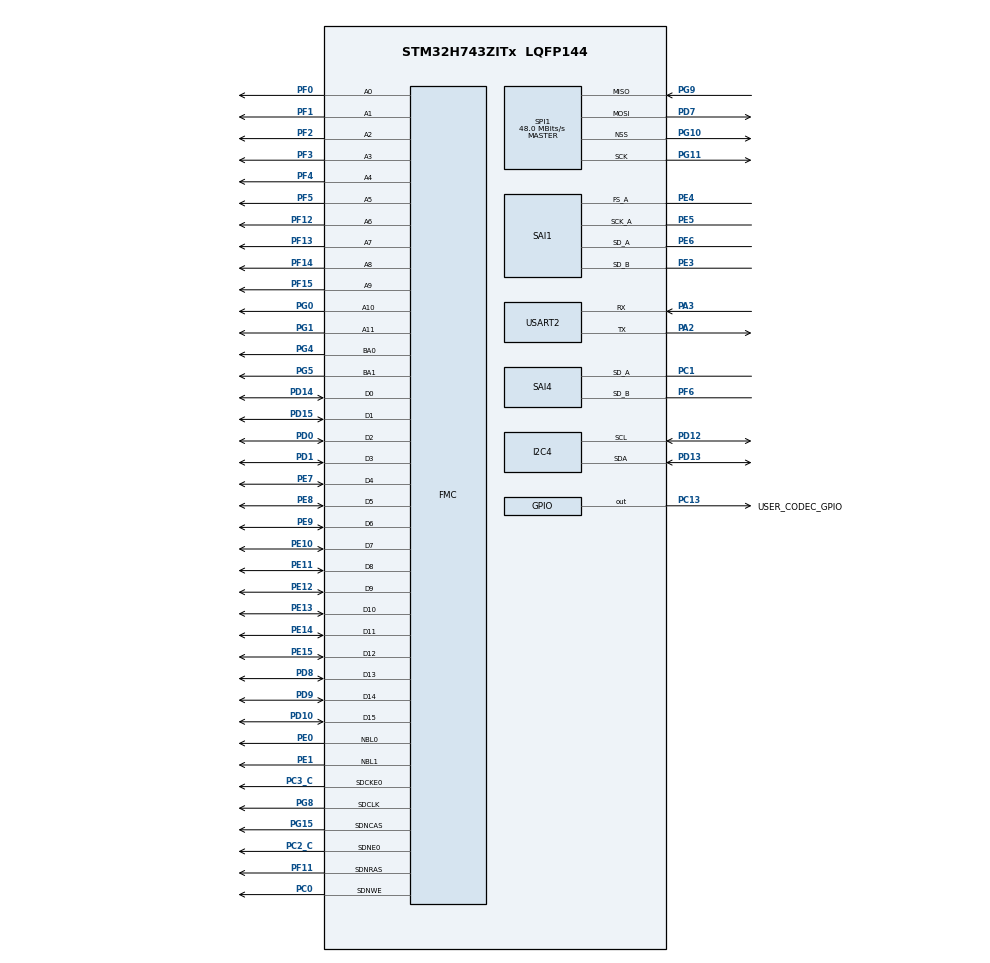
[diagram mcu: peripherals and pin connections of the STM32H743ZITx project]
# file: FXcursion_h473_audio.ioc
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Bdma.Request0=SAI4_A
Bdma.Request1=SAI4_B
Bdma.RequestsNb=2
Bdma.SAI4_A.0.Direction=DMA_PERIPH_TO_MEMORY
Bdma.SAI4_A.0.EventEnable=DISABLE
Bdma.SAI4_A.0.Instance=BDMA_Channel0
Bdma.SAI4_A.0.MemDataAlignment=DMA_MDATAALIGN_HALFWORD
Bdma.SAI4_A.0.MemInc=DMA_MINC_ENABLE
Bdma.SAI4_A.0.Mode=DMA_CIRCULAR
Bdma.SAI4_A.0.PeriphDataAlignment=DMA_PDATAALIGN_HALFWORD
Bdma.SAI4_A.0.PeriphInc=DMA_PINC_DISABLE
Bdma.SAI4_A.0.Polarity=HAL_DMAMUX_REQ_GEN_RISING
Bdma.SAI4_A.0.Priority=DMA_PRIORITY_MEDIUM
Bdma.SAI4_A.0.RequestNumber=1
Bdma.SAI4_A.0.SignalID=NONE
Bdma.SAI4_A.0.SyncEnable=DISABLE
Bdma.SAI4_A.0.SyncPolarity=HAL_DMAMUX_SYNC_NO_EVENT
Bdma.SAI4_A.0.SyncRequestNumber=1
Bdma.SAI4_A.0.SyncSignalID=NONE
Bdma.SAI4_B.1.Direction=DMA_MEMORY_TO_PERIPH
Bdma.SAI4_B.1.EventEnable=DISABLE
Bdma.SAI4_B.1.Instance=BDMA_Channel1
Bdma.SAI4_B.1.MemDataAlignment=DMA_MDATAALIGN_HALFWORD
Bdma.SAI4_B.1.MemInc=DMA_MINC_ENABLE
Bdma.SAI4_B.1.Mode=DMA_CIRCULAR
Bdma.SAI4_B.1.PeriphDataAlignment=DMA_PDATAALIGN_HALFWORD
Bdma.SAI4_B.1.PeriphInc=DMA_PINC_DISABLE
Bdma.SAI4_B.1.Polarity=HAL_DMAMUX_REQ_GEN_RISING
Bdma.SAI4_B.1.Priority=DMA_PRIORITY_MEDIUM
Bdma.SAI4_B.1.RequestNumber=1
Bdma.SAI4_B.1.SignalID=NONE
Bdma.SAI4_B.1.SyncEnable=DISABLE
Bdma.SAI4_B.1.SyncPolarity=HAL_DMAMUX_SYNC_NO_EVENT
Bdma.SAI4_B.1.SyncRequestNumber=1
Bdma.SAI4_B.1.SyncSignalID=NONE
CORTEX_M7.AccessPermission-Cortex_Memory_Protection_Unit_Region0_Settings=MPU_REGION_FULL_ACCESS
CORTEX_M7.AccessPermission-Cortex_Memory_Protection_Unit_Region1_Settings=MPU_REGION_FULL_ACCESS
CORTEX_M7.AccessPermission-Cortex_Memory_Protection_Unit_Region2_Settings=MPU_REGION_FULL_ACCESS
CORTEX_M7.BaseAddress-Cortex_Memory_Protection_Unit_Region0_Settings=0x24000000
CORTEX_M7.BaseAddress-Cortex_Memory_Protection_Unit_Region1_Settings=0xC0000000
CORTEX_M7.BaseAddress-Cortex_Memory_Protection_Unit_Region2_Settings=0x38000000
CORTEX_M7.CPU_DCache=Enabled
CORTEX_M7.CPU_ICache=Enabled
CORTEX_M7.DisableExec-Cortex_Memory_Protection_Unit_Region0_Settings=MPU_INSTRUCTION_ACCESS_DISABLE
CORTEX_M7.DisableExec-Cortex_Memory_Protection_Unit_Region2_Settings=MPU_INSTRUCTION_ACCESS_DISABLE
CORTEX_M7.Enable-Cortex_Memory_Protection_Unit_Region0_Settings=MPU_REGION_ENABLE
CORTEX_M7.Enable-Cortex_Memory_Protection_Unit_Region1_Settings=MPU_REGION_ENABLE
CORTEX_M7.Enable-Cortex_Memory_Protection_Unit_Region2_Settings=MPU_REGION_ENABLE
CORTEX_M7.IsBufferable-Cortex_Memory_Protection_Unit_Region0_Settings=MPU_ACCESS_BUFFERABLE
CORTEX_M7.IsBufferable-Cortex_Memory_Protection_Unit_Region2_Settings=MPU_ACCESS_BUFFERABLE
CORTEX_M7.IsCacheable-Cortex_Memory_Protection_Unit_Region1_Settings=MPU_ACCESS_CACHEABLE
CORTEX_M7.IsShareable-Cortex_Memory_Protection_Unit_Region0_Settings=MPU_ACCESS_SHAREABLE
CORTEX_M7.IsShareable-Cortex_Memory_Protection_Unit_Region2_Settings=MPU_ACCESS_SHAREABLE
CORTEX_M7.MPU_Control=MPU_PRIVILEGED_DEFAULT
CORTEX_M7.Size-Cortex_Memory_Protection_Unit_Region0_Settings=MPU_REGION_SIZE_8KB
CORTEX_M7.Size-Cortex_Memory_Protection_Unit_Region1_Settings=MPU_REGION_SIZE_256MB
CORTEX_M7.Size-Cortex_Memory_Protection_Unit_Region2_Settings=MPU_REGION_SIZE_64KB
Dma.Request0=SAI1_A
Dma.Request1=SAI1_B
Dma.Request2=USART2_RX
Dma.Request3=USART2_TX
Dma.Request4=SPI1_RX
Dma.Request5=SPI1_TX
Dma.SAI1_A.0.Direction=DMA_PERIPH_TO_MEMORY
Dma.SAI1_A.0.EventEnable=DISABLE
Dma.SAI1_A.0.FIFOMode=DMA_FIFOMODE_DISABLE
Dma.SAI1_A.0.Instance=DMA1_Stream0
Dma.SAI1_A.0.MemDataAlignment=DMA_MDATAALIGN_HALFWORD
Dma.SAI1_A.0.MemInc=DMA_MINC_ENABLE
Dma.SAI1_A.0.Mode=DMA_CIRCULAR
Dma.SAI1_A.0.PeriphDataAlignment=DMA_PDATAALIGN_HALFWORD
Dma.SAI1_A.0.PeriphInc=DMA_PINC_DISABLE
Dma.SAI1_A.0.Polarity=HAL_DMAMUX_REQ_GEN_RISING
Dma.SAI1_A.0.Priority=DMA_PRIORITY_MEDIUM
Dma.SAI1_A.0.RequestNumber=1
Dma.SAI1_A.0.SignalID=NONE
Dma.SAI1_A.0.SyncEnable=DISABLE
Dma.SAI1_A.0.SyncPolarity=HAL_DMAMUX_SYNC_NO_EVENT
Dma.SAI1_A.0.SyncRequestNumber=1
Dma.SAI1_A.0.SyncSignalID=NONE
Dma.SAI1_B.1.Direction=DMA_MEMORY_TO_PERIPH
Dma.SAI1_B.1.EventEnable=DISABLE
Dma.SAI1_B.1.FIFOMode=DMA_FIFOMODE_DISABLE
Dma.SAI1_B.1.Instance=DMA1_Stream1
Dma.SAI1_B.1.MemDataAlignment=DMA_MDATAALIGN_HALFWORD
Dma.SAI1_B.1.MemInc=DMA_MINC_ENABLE
Dma.SAI1_B.1.Mode=DMA_CIRCULAR
Dma.SAI1_B.1.PeriphDataAlignment=DMA_PDATAALIGN_HALFWORD
Dma.SAI1_B.1.PeriphInc=DMA_PINC_DISABLE
Dma.SAI1_B.1.Polarity=HAL_DMAMUX_REQ_GEN_RISING
Dma.SAI1_B.1.Priority=DMA_PRIORITY_MEDIUM
Dma.SAI1_B.1.RequestNumber=1
Dma.SAI1_B.1.SignalID=NONE
Dma.SAI1_B.1.SyncEnable=DISABLE
Dma.SAI1_B.1.SyncPolarity=HAL_DMAMUX_SYNC_NO_EVENT
Dma.SAI1_B.1.SyncRequestNumber=1
Dma.SAI1_B.1.SyncSignalID=NONE
Dma.SPI1_RX.4.Direction=DMA_PERIPH_TO_MEMORY
Dma.SPI1_RX.4.EventEnable=DISABLE
Dma.SPI1_RX.4.FIFOMode=DMA_FIFOMODE_DISABLE
Dma.SPI1_RX.4.Instance=DMA1_Stream4
Dma.SPI1_RX.4.MemDataAlignment=DMA_MDATAALIGN_WORD
Dma.SPI1_RX.4.MemInc=DMA_MINC_ENABLE
Dma.SPI1_RX.4.Mode=DMA_NORMAL
Dma.SPI1_RX.4.PeriphDataAlignment=DMA_PDATAALIGN_WORD
Dma.SPI1_RX.4.PeriphInc=DMA_PINC_DISABLE
Dma.SPI1_RX.4.Polarity=HAL_DMAMUX_REQ_GEN_RISING
Dma.SPI1_RX.4.Priority=DMA_PRIORITY_LOW
Dma.SPI1_RX.4.RequestNumber=1
Dma.SPI1_RX.4.SignalID=NONE
Dma.SPI1_RX.4.SyncEnable=DISABLE
Dma.SPI1_RX.4.SyncPolarity=HAL_DMAMUX_SYNC_NO_EVENT
Dma.SPI1_RX.4.SyncRequestNumber=1
Dma.SPI1_RX.4.SyncSignalID=NONE
Dma.SPI1_TX.5.Direction=DMA_MEMORY_TO_PERIPH
Dma.SPI1_TX.5.EventEnable=DISABLE
Dma.SPI1_TX.5.FIFOMode=DMA_FIFOMODE_DISABLE
Dma.SPI1_TX.5.Instance=DMA1_Stream5
Dma.SPI1_TX.5.MemDataAlignment=DMA_MDATAALIGN_WORD
Dma.SPI1_TX.5.MemInc=DMA_MINC_ENABLE
Dma.SPI1_TX.5.Mode=DMA_NORMAL
Dma.SPI1_TX.5.PeriphDataAlignment=DMA_PDATAALIGN_WORD
Dma.SPI1_TX.5.PeriphInc=DMA_PINC_DISABLE
Dma.SPI1_TX.5.Polarity=HAL_DMAMUX_REQ_GEN_RISING
Dma.SPI1_TX.5.Priority=DMA_PRIORITY_LOW
Dma.SPI1_TX.5.RequestNumber=1
Dma.SPI1_TX.5.SignalID=NONE
Dma.SPI1_TX.5.SyncEnable=DISABLE
Dma.SPI1_TX.5.SyncPolarity=HAL_DMAMUX_SYNC_NO_EVENT
Dma.SPI1_TX.5.SyncRequestNumber=1
Dma.SPI1_TX.5.SyncSignalID=NONE
Dma.USART2_RX.2.Direction=DMA_PERIPH_TO_MEMORY
Dma.USART2_RX.2.EventEnable=DISABLE
Dma.USART2_RX.2.FIFOMode=DMA_FIFOMODE_DISABLE
Dma.USART2_RX.2.Instance=DMA1_Stream2
Dma.USART2_RX.2.MemDataAlignment=DMA_MDATAALIGN_BYTE
Dma.USART2_RX.2.MemInc=DMA_MINC_ENABLE
Dma.USART2_RX.2.Mode=DMA_CIRCULAR
Dma.USART2_RX.2.PeriphDataAlignment=DMA_PDATAALIGN_BYTE
Dma.USART2_RX.2.PeriphInc=DMA_PINC_DISABLE
Dma.USART2_RX.2.Polarity=HAL_DMAMUX_REQ_GEN_RISING
Dma.USART2_RX.2.Priority=DMA_PRIORITY_LOW
Dma.USART2_RX.2.RequestNumber=1
Dma.USART2_RX.2.SignalID=NONE
Dma.USART2_RX.2.SyncEnable=DISABLE
Dma.USART2_RX.2.SyncPolarity=HAL_DMAMUX_SYNC_NO_EVENT
Dma.USART2_RX.2.SyncRequestNumber=1
Dma.USART2_RX.2.SyncSignalID=NONE
Dma.USART2_TX.3.Direction=DMA_MEMORY_TO_PERIPH
Dma.USART2_TX.3.EventEnable=DISABLE
Dma.USART2_TX.3.FIFOMode=DMA_FIFOMODE_DISABLE
Dma.USART2_TX.3.Instance=DMA1_Stream3
Dma.USART2_TX.3.MemDataAlignment=DMA_MDATAALIGN_BYTE
Dma.USART2_TX.3.MemInc=DMA_MINC_ENABLE
Dma.USART2_TX.3.Mode=DMA_NORMAL
Dma.USART2_TX.3.PeriphDataAlignment=DMA_PDATAALIGN_BYTE
Dma.USART2_TX.3.PeriphInc=DMA_PINC_DISABLE
Dma.USART2_TX.3.Polarity=HAL_DMAMUX_REQ_GEN_RISING
Dma.USART2_TX.3.Priority=DMA_PRIORITY_LOW
Dma.USART2_TX.3.RequestNumber=1
Dma.USART2_TX.3.SignalID=NONE
Dma.USART2_TX.3.SyncEnable=DISABLE
Dma.USART2_TX.3.SyncPolarity=HAL_DMAMUX_SYNC_NO_EVENT
Dma.USART2_TX.3.SyncRequestNumber=1
Dma.USART2_TX.3.SyncSignalID=NONE
FMC.CASLatency1=FMC_SDRAM_CAS_LATENCY_2
FMC.LoadToActiveDelay1=6
FMC.RCDDelay1=6
FMC.RPDelay1=6
FMC.RPDelay2=6
FMC.ReadBurst1=FMC_SDRAM_RBURST_ENABLE
FMC.ReadBurst2=FMC_SDRAM_RBURST_ENABLE
FMC.SDClockPeriod1=FMC_SDRAM_CLOCK_PERIOD_2
FMC.SDClockPeriod2=FMC_SDRAM_CLOCK_PERIOD_2
FMC.SelfRefreshTime1=11
FMC.WriteRecoveryTime1=6
I2C4.Speed=100
I2C4.Timing=0x307075B1
Mcu.Family=STM32H7
Mcu.Name=STM32H743ZITx
Mcu.Package=LQFP144
Mcu.UserConstants=MPU_D3_NONCACHABLE_0x38__,1
NVIC.BDMA_Channel0_IRQn=true\:0\:0\:false\:false\:true\:false\:true\:true
NVIC.BDMA_Channel1_IRQn=true\:0\:0\:false\:false\:true\:false\:true\:true
NVIC.DMA1_Stream0_IRQn=true\:0\:0\:false\:false\:true\:false\:true\:true
NVIC.DMA1_Stream1_IRQn=true\:0\:0\:false\:false\:true\:false\:true\:true
NVIC.DMA1_Stream2_IRQn=true\:0\:0\:false\:false\:true\:false\:true\:true
NVIC.DMA1_Stream3_IRQn=true\:0\:0\:false\:false\:true\:false\:true\:true
NVIC.DMA1_Stream4_IRQn=true\:0\:0\:false\:false\:true\:false\:true\:true
NVIC.DMA1_Stream5_IRQn=true\:0\:0\:false\:false\:true\:false\:true\:true
NVIC.PriorityGroup=NVIC_PRIORITYGROUP_4
NVIC.SAI1_IRQn=true\:0\:0\:false\:false\:true\:true\:true\:true
NVIC.SAI4_IRQn=true\:0\:0\:false\:false\:true\:true\:true\:true
NVIC.SPI1_IRQn=true\:0\:0\:false\:false\:true\:false\:true\:true
NVIC.USART2_IRQn=true\:0\:0\:false\:false\:true\:true\:true\:true
PA13\ (JTMS/SWDIO).Mode=Serial_Wire
PA13\ (JTMS/SWDIO).Signal=DEBUG_JTMS-SWDIO
PA14\ (JTCK/SWCLK).Mode=Serial_Wire
PA14\ (JTCK/SWCLK).Signal=DEBUG_JTCK-SWCLK
PA2.Mode=Asynchronous
PA2.Signal=USART2_TX
PA3.Mode=Asynchronous
PA3.Signal=USART2_RX
PC0.Signal=FMC_SDNWE
PC1.GPIO_Speed=GPIO_SPEED_FREQ_VERY_HIGH
PC1.Mode=SAI_A_SyncSlave
PC1.Signal=SAI4_SD_A
PC13.GPIO_Label=USER_CODEC_GPIO
PC13.Signal=GPIO_Output
PC2_C.Mode=SdramChipSelect1_1
PC2_C.Signal=FMC_SDNE0
PC3_C.Mode=SdramChipSelect1_1
PC3_C.Signal=FMC_SDCKE0
PD0.Signal=FMC_D2_DA2
PD1.Signal=FMC_D3_DA3
PD10.Signal=FMC_D15_DA15
PD12.GPIO_Pu=GPIO_PULLUP
PD12.Mode=I2C
PD12.Signal=I2C4_SCL
PD13.GPIO_Pu=GPIO_PULLUP
PD13.Mode=I2C
PD13.Signal=I2C4_SDA
PD14.Signal=FMC_D0_DA0
PD15.Signal=FMC_D1_DA1
PD7.GPIO_Speed=GPIO_SPEED_FREQ_VERY_HIGH
PD7.Mode=Full_Duplex_Master
PD7.Signal=SPI1_MOSI
PD8.Signal=FMC_D13_DA13
PD9.Signal=FMC_D14_DA14
PE0.Signal=FMC_NBL0
PE1.Signal=FMC_NBL1
PE10.Signal=FMC_D7_DA7
PE11.Signal=FMC_D8_DA8
PE12.Signal=FMC_D9_DA9
PE13.Signal=FMC_D10_DA10
PE14.Signal=FMC_D11_DA11
PE15.Signal=FMC_D12_DA12
PE3.GPIO_Speed=GPIO_SPEED_FREQ_VERY_HIGH
PE3.Mode=SAI_B_SyncSlave
PE3.Signal=SAI1_SD_B
PE4.GPIO_Speed=GPIO_SPEED_FREQ_VERY_HIGH
PE4.Mode=SAI_A_AsyncSlave
PE4.Signal=SAI1_FS_A
PE5.GPIO_Speed=GPIO_SPEED_FREQ_VERY_HIGH
PE5.Mode=SAI_A_AsyncSlave
PE5.Signal=SAI1_SCK_A
PE6.GPIO_Speed=GPIO_SPEED_FREQ_VERY_HIGH
PE6.Mode=SAI_A_AsyncSlave
PE6.Signal=SAI1_SD_A
PE7.Signal=FMC_D4_DA4
PE8.Signal=FMC_D5_DA5
PE9.Signal=FMC_D6_DA6
PF0.Signal=FMC_A0
PF1.Signal=FMC_A1
PF11.Signal=FMC_SDNRAS
PF12.Signal=FMC_A6
PF13.Signal=FMC_A7
PF14.Signal=FMC_A8
PF15.Signal=FMC_A9
PF2.Signal=FMC_A2
PF3.Signal=FMC_A3
PF4.Signal=FMC_A4
PF5.Signal=FMC_A5
PF6.GPIO_Speed=GPIO_SPEED_FREQ_VERY_HIGH
PF6.Mode=SAI_B_SyncSlave
PF6.Signal=SAI4_SD_B
PG0.Signal=FMC_A10
PG1.Signal=FMC_A11
PG10.GPIO_Speed=GPIO_SPEED_FREQ_VERY_HIGH
PG10.Mode=NSS_Signal_Hard_Output
PG10.Signal=SPI1_NSS
PG11.GPIO_Speed=GPIO_SPEED_FREQ_VERY_HIGH
PG11.Mode=Full_Duplex_Master
PG11.Signal=SPI1_SCK
PG15.Signal=FMC_SDNCAS
PG4.Signal=FMC_A14_BA0
PG5.Signal=FMC_A15_BA1
PG8.Signal=FMC_SDCLK
PG9.GPIO_Speed=GPIO_SPEED_FREQ_VERY_HIGH
PG9.Mode=Full_Duplex_Master
PG9.Signal=SPI1_MISO
ProjectManager.HeapSize=0x200
ProjectManager.StackSize=0x400
ProjectManager.TargetToolchain=STM32CubeIDE
RCC.ADCFreq_Value=12288000
RCC.APB1Freq_Value=120000000
RCC.APB2Freq_Value=120000000
RCC.APB3Freq_Value=120000000
RCC.APB4Freq_Value=120000000
RCC.CortexFreq_Value=480000000
RCC.D1PPRE=RCC_APB3_DIV2
RCC.D2PPRE1=RCC_APB1_DIV2
RCC.D2PPRE2=RCC_APB2_DIV2
RCC.D3PPRE=RCC_APB4_DIV2
RCC.DIVM1=2
RCC.DIVM2=10
RCC.DIVM3=8
RCC.DIVN1=120
RCC.DIVN2=192
RCC.DIVN3=96
RCC.DIVP2=25
RCC.DIVQ3=4
RCC.HCLKFreq_Value=240000000
RCC.HPRE=RCC_HCLK_DIV2
RCC.HSIDiv=RCC_PLLSAIDIVR_4
RCC.PLL2FRACN=0
RCC.PLL3FRACN=0
RCC.PLLFRACN=0
RCC.SAI1CLockSelection=RCC_SAI1CLKSOURCE_PLL2
RCC.SAI4ACLockSelection=RCC_SAI4ACLKSOURCE_PLL2
RCC.SAI4BCLockSelection=RCC_SAI4BCLKSOURCE_PLL2
RCC.SPI123CLockSelection=RCC_SPI123CLKSOURCE_PLL3
RCC.SYSCLKFreq_VALUE=480000000
RCC.SYSCLKSource=RCC_SYSCLKSOURCE_PLLCLK
RCC.USBFreq_Value=480000000
SAI1.AudioMode-SAI_A_AsyncSlave=SAI_MODESLAVE_RX
SAI1.AudioMode-SAI_B_SyncSlave=SAI_MODESLAVE_TX
SAI1.BasicDataSize-SAI_A_AsyncSlave=SAI_PROTOCOL_DATASIZE_16BITEXTENDED
SAI1.BasicDataSize-SAI_B_SyncSlave=SAI_PROTOCOL_DATASIZE_16BITEXTENDED
SAI1.InitProtocol-SAI_A_AsyncSlave=Enable
SAI1.InitProtocol-SAI_B_SyncSlave=Enable
SAI1.Instance-SAI_A_AsyncSlave=SAI$Index_Block_A
SAI1.Instance-SAI_B_SyncSlave=SAI$Index_Block_B
SAI1.SynchroExt=SAI_SYNCEXT_OUTBLOCKA_ENABLE
SAI1.VirtualMode-SAI_A_AsyncSlave=VM_SLAVE
SAI1.VirtualMode-SAI_B_SyncSlave=VM_SLAVE
SAI1.VirtualProtocol-SAI_A_BASIC=VM_BASIC_PROTOCOL
SAI1.VirtualProtocol-SAI_B_BASIC=VM_BASIC_PROTOCOL
SAI4.AudioMode-SAI_B_SyncSlave=SAI_MODESLAVE_TX
SAI4.BasicDataSize-SAI_A_SyncSlave=SAI_PROTOCOL_DATASIZE_16BITEXTENDED
SAI4.BasicDataSize-SAI_B_SyncSlave=SAI_PROTOCOL_DATASIZE_16BITEXTENDED
SAI4.InitProtocol-SAI_A_SyncSlave=Enable
SAI4.InitProtocol-SAI_B_SyncSlave=Enable
SAI4.Instance-SAI_A_SyncSlave=SAI$Index_Block_A
SAI4.Instance-SAI_B_SyncSlave=SAI$Index_Block_B
SAI4.Synchro_A=SAI_SYNCHRONOUS_EXT_SAI1
SAI4.Synchro_B=SAI_SYNCHRONOUS_EXT_SAI1
SAI4.VirtualMode-SAI_A_SyncSlave=VM_SLAVE
SAI4.VirtualMode-SAI_B_SyncSlave=VM_SLAVE
SAI4.VirtualProtocol-SAI_A_BASIC=VM_BASIC_PROTOCOL
SAI4.VirtualProtocol-SAI_B_BASIC=VM_BASIC_PROTOCOL
SH.FMC_A0.0=FMC_A0,12b-sda1
SH.FMC_A1.0=FMC_A1,12b-sda1
SH.FMC_A10.0=FMC_A10,12b-sda1
SH.FMC_A11.0=FMC_A11,12b-sda1
SH.FMC_A14_BA0.0=FMC_BA0,FourSdramBanks1
SH.FMC_A15_BA1.0=FMC_BA1,FourSdramBanks1
SH.FMC_A2.0=FMC_A2,12b-sda1
SH.FMC_A3.0=FMC_A3,12b-sda1
SH.FMC_A4.0=FMC_A4,12b-sda1
SH.FMC_A5.0=FMC_A5,12b-sda1
SH.FMC_A6.0=FMC_A6,12b-sda1
SH.FMC_A7.0=FMC_A7,12b-sda1
SH.FMC_A8.0=FMC_A8,12b-sda1
SH.FMC_A9.0=FMC_A9,12b-sda1
SH.FMC_D0_DA0.0=FMC_D0,sd-16b-d1
SH.FMC_D10_DA10.0=FMC_D10,sd-16b-d1
SH.FMC_D11_DA11.0=FMC_D11,sd-16b-d1
SH.FMC_D12_DA12.0=FMC_D12,sd-16b-d1
SH.FMC_D13_DA13.0=FMC_D13,sd-16b-d1
SH.FMC_D14_DA14.0=FMC_D14,sd-16b-d1
SH.FMC_D15_DA15.0=FMC_D15,sd-16b-d1
SH.FMC_D1_DA1.0=FMC_D1,sd-16b-d1
SH.FMC_D2_DA2.0=FMC_D2,sd-16b-d1
SH.FMC_D3_DA3.0=FMC_D3,sd-16b-d1
SH.FMC_D4_DA4.0=FMC_D4,sd-16b-d1
SH.FMC_D5_DA5.0=FMC_D5,sd-16b-d1
SH.FMC_D6_DA6.0=FMC_D6,sd-16b-d1
SH.FMC_D7_DA7.0=FMC_D7,sd-16b-d1
SH.FMC_D8_DA8.0=FMC_D8,sd-16b-d1
SH.FMC_D9_DA9.0=FMC_D9,sd-16b-d1
SH.FMC_NBL0.0=FMC_NBL0,Sd2ByteEnable1
SH.FMC_NBL1.0=FMC_NBL1,Sd2ByteEnable1
SH.FMC_SDCLK.0=FMC_SDCLK,12b-sda1
SH.FMC_SDNCAS.0=FMC_SDNCAS,12b-sda1
SH.FMC_SDNRAS.0=FMC_SDNRAS,12b-sda1
SH.FMC_SDNWE.0=FMC_SDNWE,12b-sda1
SPI1.CalculateBaudRate=48.0 MBits/s
SPI1.DataSize=SPI_DATASIZE_32BIT
SPI1.Direction=SPI_DIRECTION_2LINES
SPI1.Mode=SPI_MODE_MASTER
SPI1.VirtualNSS=VM_NSSHARD
SPI1.VirtualType=VM_MASTER
USART2.VirtualMode-Asynchronous=VM_ASYNC
VP_SAI1_VP_$IpInstance_SAIA_SAI_BASIC.Mode=SAI_A_BASIC
VP_SAI1_VP_$IpInstance_SAIB_SAI_BASIC.Mode=SAI_B_BASIC
VP_SAI1_VP_$IpInstance_SYNCHRO_EXTERNAL.Mode=SynchroExternal
VP_SAI4_VP_$IpInstance_SAIA_SAI_BASIC.Mode=SAI_A_BASIC
VP_SAI4_VP_$IpInstance_SAIB_SAI_BASIC.Mode=SAI_B_BASIC
board=custom

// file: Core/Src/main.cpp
/* USER CODE BEGIN Header */
/**
  ******************************************************************************
  * @file           : main.c
  * @brief          : Main program body
  ******************************************************************************
  * @attention
  *
  * Copyright (c) 2024 STMicroelectronics.
  * All rights reserved.
  *
  * This software is licensed under terms that can be found in the LICENSE file
  * in the root directory of this software component.
  * If no LICENSE file comes with this software, it is provided AS-IS.
  *
  ******************************************************************************
  */
/* USER CODE END Header */
#include "main.h"
#include "bdma.h"
#include "dma.h"
#include "i2c.h"
#include "sai.h"
#include "spi.h"
#include "usart.h"
#include "gpio.h"
#include "fmc.h"

/* USER CODE BEGIN Includes */
#include "Handy.h"
#include "../../Drivers/HW/wm8731.h"
#include "../../HW/GUIadapter.h"
#include "../../Modules/AudioSys.hpp"
/* USER CODE END Includes */

void SystemClock_Config(void);
void PeriphCommonClock_Config(void);
static void MPU_Config(void);

int main(void)
{

  /* MPU Configuration--------------------------------------------------------*/
  MPU_Config();
/* Enable the CPU Cache */

  /* Enable I-Cache---------------------------------------------------------*/
  SCB_EnableICache();

  /* Enable D-Cache---------------------------------------------------------*/
  SCB_EnableDCache();

  /* MCU Configuration--------------------------------------------------------*/

  /* Reset of all peripherals, Initializes the Flash interface and the Systick. */
  HAL_Init();

  /* Configure the system clock */
  SystemClock_Config();

/* Configure the peripherals common clocks */
  PeriphCommonClock_Config();

  /* Initialize all configured peripherals */
  MX_GPIO_Init();
  MX_DMA_Init();
  MX_BDMA_Init();
  MX_FMC_Init();
  MX_SAI4_Init();
  MX_SAI1_Init();

  MX_I2C4_Init();
  MX_USART2_UART_Init();
  MX_SPI1_Init();
  /* USER CODE BEGIN 2 */
//  uint8_t data = 0x6D;
//  uint8_t a = 1;
//  while(a!=HAL_OK) {
//	  for(uint8_t i = 0; i<0x7F; i++) {
//		   a = HAL_I2C_Mem_Write(&hi2c4, i<<1, 0x01,CODEC_MEMADD_SIZE, &data, 1, 20);
//  	  }
//  }

	CodecPowerUp(CODEC_ADDRESS_0);
	SetHPGain(-8, CODEC_ADDRESS_0);

	CodecPowerUp(CODEC_ADDRESS_1);
	SetHPGain(-8, CODEC_ADDRESS_1);

//	CodecPowerUp(CODEC_ADDRESS_0);
//	SetHPGain(-8, CODEC_ADDRESS_0);

	saiAdapter_Init(&sai4adapter, HW_SAI4);
	saiAdapter_Init(&sai1adapter, HW_SAI1);

	audioSystem.includeModules();
	guiAdapter_Init(&guiadapter);

  /* USER CODE END 2 */

  /* Infinite loop */
  /* USER CODE BEGIN WHILE */
  while (1)
  {
    audioSystem.update();
    /* USER CODE END WHILE */

  }
}

void SystemClock_Config(void)
{
  RCC_OscInitTypeDef RCC_OscInitStruct = {0};
  RCC_ClkInitTypeDef RCC_ClkInitStruct = {0};

  /** Supply configuration update enable
  */
  HAL_PWREx_ConfigSupply(PWR_LDO_SUPPLY);

  /** Configure the main internal regulator output voltage
  */
  __HAL_PWR_VOLTAGESCALING_CONFIG(PWR_REGULATOR_VOLTAGE_SCALE1);

  while(!__HAL_PWR_GET_FLAG(PWR_FLAG_VOSRDY)) {}

  __HAL_RCC_SYSCFG_CLK_ENABLE();
  __HAL_PWR_VOLTAGESCALING_CONFIG(PWR_REGULATOR_VOLTAGE_SCALE0);

  while(!__HAL_PWR_GET_FLAG(PWR_FLAG_VOSRDY)) {}

  /** Initializes the RCC Oscillators according to the specified parameters
  * in the RCC_OscInitTypeDef structure.
  */
  RCC_OscInitStruct.OscillatorType = RCC_OSCILLATORTYPE_HSI;
  RCC_OscInitStruct.HSIState = RCC_HSI_DIV4;
  RCC_OscInitStruct.HSICalibrationValue = RCC_HSICALIBRATION_DEFAULT;
  RCC_OscInitStruct.PLL.PLLState = RCC_PLL_ON;
  RCC_OscInitStruct.PLL.PLLSource = RCC_PLLSOURCE_HSI;
  RCC_OscInitStruct.PLL.PLLM = 2;
  RCC_OscInitStruct.PLL.PLLN = 120;
  RCC_OscInitStruct.PLL.PLLP = 2;
  RCC_OscInitStruct.PLL.PLLQ = 2;
  RCC_OscInitStruct.PLL.PLLR = 2;
  RCC_OscInitStruct.PLL.PLLRGE = RCC_PLL1VCIRANGE_3;
  RCC_OscInitStruct.PLL.PLLVCOSEL = RCC_PLL1VCOWIDE;
  RCC_OscInitStruct.PLL.PLLFRACN = 0;
  if (HAL_RCC_OscConfig(&RCC_OscInitStruct) != HAL_OK)
  {
    Error_Handler();
  }

  /** Initializes the CPU, AHB and APB buses clocks
  */
  RCC_ClkInitStruct.ClockType = RCC_CLOCKTYPE_HCLK|RCC_CLOCKTYPE_SYSCLK
                              |RCC_CLOCKTYPE_PCLK1|RCC_CLOCKTYPE_PCLK2
                              |RCC_CLOCKTYPE_D3PCLK1|RCC_CLOCKTYPE_D1PCLK1;
  RCC_ClkInitStruct.SYSCLKSource = RCC_SYSCLKSOURCE_PLLCLK;
  RCC_ClkInitStruct.SYSCLKDivider = RCC_SYSCLK_DIV1;
  RCC_ClkInitStruct.AHBCLKDivider = RCC_HCLK_DIV2;
  RCC_ClkInitStruct.APB3CLKDivider = RCC_APB3_DIV2;
  RCC_ClkInitStruct.APB1CLKDivider = RCC_APB1_DIV2;
  RCC_ClkInitStruct.APB2CLKDivider = RCC_APB2_DIV2;
  RCC_ClkInitStruct.APB4CLKDivider = RCC_APB4_DIV2;

  if (HAL_RCC_ClockConfig(&RCC_ClkInitStruct, FLASH_LATENCY_4) != HAL_OK)
  {
    Error_Handler();
  }
}

void PeriphCommonClock_Config(void)
{
  RCC_PeriphCLKInitTypeDef PeriphClkInitStruct = {0};

  /** Initializes the peripherals clock
  */
  PeriphClkInitStruct.PeriphClockSelection = RCC_PERIPHCLK_SAI4A|RCC_PERIPHCLK_SAI4B
                              |RCC_PERIPHCLK_SAI1;
  PeriphClkInitStruct.PLL2.PLL2M = 10;
  PeriphClkInitStruct.PLL2.PLL2N = 192;
  PeriphClkInitStruct.PLL2.PLL2P = 25;
  PeriphClkInitStruct.PLL2.PLL2Q = 2;
  PeriphClkInitStruct.PLL2.PLL2R = 2;
  PeriphClkInitStruct.PLL2.PLL2RGE = RCC_PLL2VCIRANGE_0;
  PeriphClkInitStruct.PLL2.PLL2VCOSEL = RCC_PLL2VCOWIDE;
  PeriphClkInitStruct.PLL2.PLL2FRACN = 0;
  PeriphClkInitStruct.Sai1ClockSelection = RCC_SAI1CLKSOURCE_PLL2;
  PeriphClkInitStruct.Sai4AClockSelection = RCC_SAI4ACLKSOURCE_PLL2;
  PeriphClkInitStruct.Sai4BClockSelection = RCC_SAI4BCLKSOURCE_PLL2;
  if (HAL_RCCEx_PeriphCLKConfig(&PeriphClkInitStruct) != HAL_OK)
  {
    Error_Handler();
  }
}

/* MPU Configuration */

void MPU_Config(void)
{
  MPU_Region_InitTypeDef MPU_InitStruct = {0};

  /* Disables the MPU */
  HAL_MPU_Disable();

  /** Initializes and configures the Region and the memory to be protected
  */
  MPU_InitStruct.Enable = MPU_REGION_ENABLE;
  MPU_InitStruct.Number = MPU_REGION_NUMBER0;
  MPU_InitStruct.BaseAddress = 0x24000000;
  MPU_InitStruct.Size = MPU_REGION_SIZE_8KB;
  MPU_InitStruct.SubRegionDisable = 0x0;
  MPU_InitStruct.TypeExtField = MPU_TEX_LEVEL0;
  MPU_InitStruct.AccessPermission = MPU_REGION_FULL_ACCESS;
  MPU_InitStruct.DisableExec = MPU_INSTRUCTION_ACCESS_DISABLE;
  MPU_InitStruct.IsShareable = MPU_ACCESS_SHAREABLE;
  MPU_InitStruct.IsCacheable = MPU_ACCESS_NOT_CACHEABLE;
  MPU_InitStruct.IsBufferable = MPU_ACCESS_BUFFERABLE;

  HAL_MPU_ConfigRegion(&MPU_InitStruct);

  /** Initializes and configures the Region and the memory to be protected
  */
  MPU_InitStruct.Number = MPU_REGION_NUMBER1;
  MPU_InitStruct.BaseAddress = 0xC0000000;
  MPU_InitStruct.Size = MPU_REGION_SIZE_256MB;
  MPU_InitStruct.DisableExec = MPU_INSTRUCTION_ACCESS_ENABLE;
  MPU_InitStruct.IsShareable = MPU_ACCESS_NOT_SHAREABLE;
  MPU_InitStruct.IsCacheable = MPU_ACCESS_CACHEABLE;
  MPU_InitStruct.IsBufferable = MPU_ACCESS_NOT_BUFFERABLE;

  HAL_MPU_ConfigRegion(&MPU_InitStruct);

  /** Initializes and configures the Region and the memory to be protected
  */
  MPU_InitStruct.Number = MPU_REGION_NUMBER2;
  MPU_InitStruct.BaseAddress = 0x38000000;
  MPU_InitStruct.Size = MPU_REGION_SIZE_64KB;
  MPU_InitStruct.DisableExec = MPU_INSTRUCTION_ACCESS_DISABLE;
  MPU_InitStruct.IsShareable = MPU_ACCESS_SHAREABLE;
  MPU_InitStruct.IsCacheable = MPU_ACCESS_NOT_CACHEABLE;
  MPU_InitStruct.IsBufferable = MPU_ACCESS_BUFFERABLE;

  HAL_MPU_ConfigRegion(&MPU_InitStruct);
  /* Enables the MPU */
  HAL_MPU_Enable(MPU_PRIVILEGED_DEFAULT);

}

void Error_Handler(void)
{
  __disable_irq();
  while (1)
  {
  }
}
